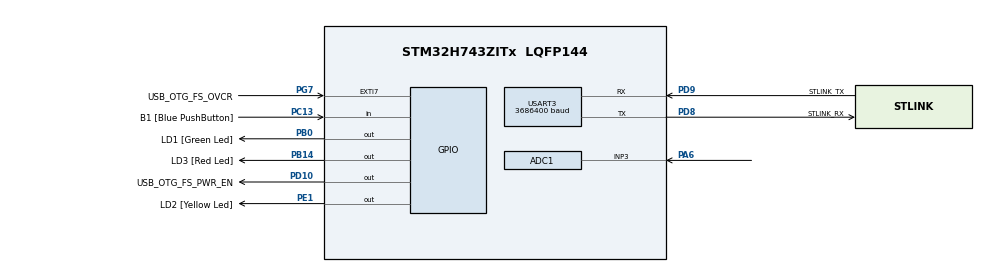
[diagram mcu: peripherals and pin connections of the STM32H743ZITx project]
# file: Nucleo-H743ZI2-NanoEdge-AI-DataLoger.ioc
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ADC1.Channel-0\#ChannelRegularConversion=ADC_CHANNEL_3
ADC1.ExternalTrigConv=ADC_EXTERNALTRIG_T6_TRGO
ADC1.NbrOfConversionFlag=1
ADC1.OffsetNumber-0\#ChannelRegularConversion=ADC_OFFSET_NONE
ADC1.OffsetSignedSaturation-0\#ChannelRegularConversion=DISABLE
ADC1.Rank-0\#ChannelRegularConversion=1
ADC1.Resolution=ADC_RESOLUTION_16B
ADC1.SamplingTime-0\#ChannelRegularConversion=ADC_SAMPLETIME_1CYCLE_5
ADC1.master=1
Mcu.Family=STM32H7
Mcu.Name=STM32H743ZITx
Mcu.Package=LQFP144
NVIC.ADC_IRQn=true\:0\:0\:false\:false\:true\:true\:true\:true
NVIC.PriorityGroup=NVIC_PRIORITYGROUP_4
NVIC.TIM6_DAC_IRQn=true\:0\:0\:false\:false\:true\:true\:true\:true
PA1.Signal=ETH_REF_CLK
PA11.Signal=USB_OTG_FS_DM
PA12.Signal=USB_OTG_FS_DP
PA13\ (JTMS/SWDIO).Mode=Serial_Wire
PA13\ (JTMS/SWDIO).Signal=DEBUG_JTMS-SWDIO
PA14\ (JTCK/SWCLK).Mode=Serial_Wire
PA14\ (JTCK/SWCLK).Signal=DEBUG_JTCK-SWCLK
PA2.Signal=ETH_MDIO
PA6.Signal=ADCx_INP3
PA7.Signal=ETH_CRS_DV
PA8.Signal=USB_OTG_FS_SOF
PA9.Signal=USB_OTG_FS_VBUS
PB0.GPIO_Label=LD1 [Green Led]
PB0.GPIO_Speed=GPIO_SPEED_FREQ_VERY_HIGH
PB0.Signal=GPIO_Output
PB13.Signal=ETH_TXD1
PB14.GPIO_Label=LD3 [Red Led]
PB14.GPIO_Speed=GPIO_SPEED_FREQ_VERY_HIGH
PB14.Signal=GPIO_Output
PC1.Signal=ETH_MDC
PC13.GPIO_Label=B1 [Blue PushButton]
PC13.Signal=GPIO_Input
PC14-OSC32_IN\ (OSC32_IN).Signal=RCC_OSC32_IN
PC15-OSC32_OUT\ (OSC32_OUT).Signal=RCC_OSC32_OUT
PC4.Signal=ETH_RXD0
PC5.Signal=ETH_RXD1
PD10.GPIO_Label=USB_OTG_FS_PWR_EN
PD10.Signal=GPIO_Output
PD8.GPIO_Label=STLINK_RX
PD8.Mode=Asynchronous
PD8.Signal=USART3_TX
PD9.GPIO_Label=STLINK_TX
PD9.Mode=Asynchronous
PD9.Signal=USART3_RX
PE1.GPIO_Label=LD2 [Yellow Led]
PE1.GPIO_Speed=GPIO_SPEED_FREQ_VERY_HIGH
PE1.Signal=GPIO_Output
PG11.Signal=ETH_TX_EN
PG13.Signal=ETH_TXD0
PG7.GPIO_Label=USB_OTG_FS_OVCR
PG7.Signal=GPXTI7
PH0-OSC_IN\ (PH0).Signal=RCC_OSC_IN
PH1-OSC_OUT\ (PH1).Signal=RCC_OSC_OUT
ProjectManager.HeapSize=0x800
ProjectManager.StackSize=0x800
ProjectManager.TargetToolchain=EWARM V8.50
RCC.ADCFreq_Value=100000000
RCC.APB1Freq_Value=120000000
RCC.APB2Freq_Value=120000000
RCC.APB3Freq_Value=120000000
RCC.APB4Freq_Value=120000000
RCC.CortexFreq_Value=480000000
RCC.D1PPRE=RCC_APB3_DIV2
RCC.D2PPRE1=RCC_APB1_DIV2
RCC.D2PPRE2=RCC_APB2_DIV2
RCC.D3PPRE=RCC_APB4_DIV2
RCC.DIVM1=4
RCC.DIVM2=8
RCC.DIVM3=8
RCC.DIVN1=480
RCC.DIVN2=200
RCC.DIVN3=150
RCC.DIVQ1=4
RCC.HCLKFreq_Value=240000000
RCC.HPRE=RCC_HCLK_DIV2
RCC.HSE_VALUE=8000000
RCC.HSIDiv=RCC_PLLSAIDIVR_8
RCC.PLLFRACN=0
RCC.PWR_Regulator_Voltage_Scale=PWR_REGULATOR_VOLTAGE_SCALE0
RCC.SYSCLKFreq_VALUE=480000000
RCC.SYSCLKSource=RCC_SYSCLKSOURCE_PLLCLK
RCC.USBCLockSelection=RCC_USBCLKSOURCE_HSI48
RCC.USBFreq_Value=48000000
SH.ADCx_INP3.0=ADC1_INP3,IN3-Single-Ended
TIM6.Period=39
TIM6.Prescaler=239
TIM6.TIM_MasterOutputTrigger=TIM_TRGO_UPDATE
USART3.BaudRate=3686400
USART3.VirtualMode-Asynchronous=VM_ASYNC
VP_MEMORYMAP_VS_MEMORYMAP.Mode=CurAppReg
VP_TIM6_VS_ClockSourceINT.Mode=Enable_Timer
board=NUCLEO-H743ZI2

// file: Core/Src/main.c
/* USER CODE BEGIN Header */
/**
  ******************************************************************************
  * @file           : main.c
  * @brief          : Main program body
  ******************************************************************************
  * @attention
  *
  * Copyright (c) 2025 STMicroelectronics.
  * All rights reserved.
  *
  * This software is licensed under terms that can be found in the LICENSE file
  * in the root directory of this software component.
  * If no LICENSE file comes with this software, it is provided AS-IS.
  *
  ******************************************************************************
  */
/* USER CODE END Header */
#include "main.h"

/* USER CODE BEGIN Includes */

#include <string.h>
#include <stdio.h>

/* USER CODE END Includes */

ADC_HandleTypeDef hadc1;

TIM_HandleTypeDef htim6;

UART_HandleTypeDef huart3;

void SystemClock_Config(void);
static void MX_GPIO_Init(void);
static void MX_ADC1_Init(void);
static void MX_USART3_UART_Init(void);
static void MX_TIM6_Init(void);

/* USER CODE BEGIN 0 */

//#define TX_BUFFER_SIZE  512U
#define TX_BUFFER_SIZE  1024U
//#define TX_BUFFER_SIZE  4096U

#define ADC_BUF1_SELECT (0)
#define ADC_BUF2_SELECT (1)

uint32_t adc_buf_selector = ADC_BUF1_SELECT;

uint32_t adc_buf_index = 0;

uint32_t adc_buf1[TX_BUFFER_SIZE];
uint32_t adc_buf2[TX_BUFFER_SIZE];

uint32_t adc_buf1_loaded = 0;
uint32_t adc_buf2_loaded = 0;

uint8_t uart_tx_buf[128];

void overload_error(void)
{
    while(1)
    {
        __NOP();
        __NOP();
        __NOP();
        __NOP();
        __NOP();
    }
}

void HAL_TIM_PeriodElapsedCallback(TIM_HandleTypeDef *htim)
{
    if (htim == &htim6)
    {

        // HAL_GPIO_WritePin( LD1_GPIO_Port, LD1_Pin, GPIO_PIN_SET );
        HAL_GPIO_TogglePin( LD1_GPIO_Port, LD1_Pin);

        if ( adc_buf_selector == ADC_BUF1_SELECT )
        {
            adc_buf1[adc_buf_index] = HAL_ADC_GetValue(&hadc1);

            adc_buf_index ++;

            if ( adc_buf_index >= TX_BUFFER_SIZE )
            {
                adc_buf_index = 0;

                if ( adc_buf2_loaded )
                {
                    // ERROR
                    overload_error();
                }

                adc_buf1_loaded = 1;

                adc_buf_selector = ADC_BUF2_SELECT;
            }
        }
        else
        {
            adc_buf2[adc_buf_index] = HAL_ADC_GetValue(&hadc1);

            adc_buf_index ++;

            if ( adc_buf_index >= TX_BUFFER_SIZE )
            {
                adc_buf_index = 0;

                if ( adc_buf1_loaded )
                {
                    // ERROR
                    overload_error();
                }

                adc_buf2_loaded = 1;

                adc_buf_selector = ADC_BUF1_SELECT;
            }
        }

        __NOP();
        __NOP();
        __NOP();
        __NOP();
    }
}

void HAL_ADC_ConvCpltCallback(ADC_HandleTypeDef *hadc)
{
    if (hadc == &hadc1)
    {
        __NOP();
        __NOP();
        __NOP();
        __NOP();
    }
}

uint32_t i = 0;
int msg_len = 0;
GPIO_PinState MyButton;
float Valuefl = 0;

/* USER CODE END 0 */

int main(void)
{

  /* MCU Configuration--------------------------------------------------------*/

  /* Reset of all peripherals, Initializes the Flash interface and the Systick. */
  HAL_Init();

  /* Configure the system clock */
  SystemClock_Config();

  /* Initialize all configured peripherals */
  MX_GPIO_Init();
  MX_ADC1_Init();
  MX_USART3_UART_Init();
  MX_TIM6_Init();

  /* Infinite loop */
  /* USER CODE BEGIN WHILE */

  HAL_ADCEx_Calibration_Start( &hadc1, ADC_CALIB_OFFSET, ADC_SINGLE_ENDED);

  HAL_ADCEx_Calibration_Start( &hadc1, ADC_CALIB_OFFSET_LINEARITY, ADC_SINGLE_ENDED);

  HAL_TIM_Base_Start_IT(&htim6);

  if(HAL_ADC_Start_IT(&hadc1) != HAL_OK)
  {
      Error_Handler();
  }

  while (1)
  {

      MyButton = HAL_GPIO_ReadPin( B1_GPIO_Port, B1_Pin );

      if ( MyButton == GPIO_PIN_RESET )
      {
          HAL_GPIO_WritePin( LD3_GPIO_Port, LD3_Pin, GPIO_PIN_SET );
      }
      else
      {
          HAL_GPIO_WritePin( LD3_GPIO_Port, LD3_Pin, GPIO_PIN_RESET );
      }

      // send ADC data to USART

      // Send buffer 1

      if ( adc_buf1_loaded )
      {
          HAL_GPIO_WritePin(LD2_GPIO_Port, LD2_Pin, GPIO_PIN_RESET);

          for ( i = 0; i < TX_BUFFER_SIZE; i++)
          {
              Valuefl = adc_buf1[i] * (3.3f/65536.0f);

              if ( i < (TX_BUFFER_SIZE-1) )
              {
                  msg_len = sprintf( (char*)uart_tx_buf, "%.4f ", Valuefl) ;

                  HAL_UART_Transmit( &huart3, uart_tx_buf, msg_len, 1 );
              }
              else
              {
                  msg_len = sprintf( (char*)uart_tx_buf, "%.4f\n", Valuefl) ;

                  HAL_UART_Transmit( &huart3, uart_tx_buf, msg_len, 1 );
              }
          }

          adc_buf1_loaded = 0;

          HAL_GPIO_WritePin(LD2_GPIO_Port, LD2_Pin, GPIO_PIN_SET);
      }

       // Send buffer 2

      if ( adc_buf2_loaded )
      {
         HAL_GPIO_WritePin(LD2_GPIO_Port, LD2_Pin, GPIO_PIN_RESET);

          for ( i = 0; i < TX_BUFFER_SIZE; i++)
          {
              Valuefl = adc_buf2[i] * (3.3f/65536.0f);

              if ( i < (TX_BUFFER_SIZE-1) )
              {
                  msg_len = sprintf( (char*)uart_tx_buf, "%.4f ", Valuefl) ;

                  HAL_UART_Transmit( &huart3, uart_tx_buf, msg_len, 1 );
              }
              else
              {
                  msg_len = sprintf( (char*)uart_tx_buf, "%.4f\n", Valuefl) ;

                  HAL_UART_Transmit( &huart3, uart_tx_buf, msg_len, 1 );
              }
          }

          adc_buf2_loaded = 0;

          HAL_GPIO_WritePin(LD2_GPIO_Port, LD2_Pin, GPIO_PIN_SET);
      }

    /* USER CODE END WHILE */

  }
}

void SystemClock_Config(void)
{
  RCC_OscInitTypeDef RCC_OscInitStruct = {0};
  RCC_ClkInitTypeDef RCC_ClkInitStruct = {0};

  /** Supply configuration update enable
  */
  HAL_PWREx_ConfigSupply(PWR_LDO_SUPPLY);

  /** Configure the main internal regulator output voltage
  */
  __HAL_PWR_VOLTAGESCALING_CONFIG(PWR_REGULATOR_VOLTAGE_SCALE1);

  while(!__HAL_PWR_GET_FLAG(PWR_FLAG_VOSRDY)) {}

  __HAL_RCC_SYSCFG_CLK_ENABLE();
  __HAL_PWR_VOLTAGESCALING_CONFIG(PWR_REGULATOR_VOLTAGE_SCALE0);

  while(!__HAL_PWR_GET_FLAG(PWR_FLAG_VOSRDY)) {}

  /** Initializes the RCC Oscillators according to the specified parameters
  * in the RCC_OscInitTypeDef structure.
  */
  RCC_OscInitStruct.OscillatorType = RCC_OSCILLATORTYPE_HSI;
  RCC_OscInitStruct.HSIState = RCC_HSI_DIV8;
  RCC_OscInitStruct.HSICalibrationValue = RCC_HSICALIBRATION_DEFAULT;
  RCC_OscInitStruct.PLL.PLLState = RCC_PLL_ON;
  RCC_OscInitStruct.PLL.PLLSource = RCC_PLLSOURCE_HSI;
  RCC_OscInitStruct.PLL.PLLM = 4;
  RCC_OscInitStruct.PLL.PLLN = 480;
  RCC_OscInitStruct.PLL.PLLP = 2;
  RCC_OscInitStruct.PLL.PLLQ = 4;
  RCC_OscInitStruct.PLL.PLLR = 2;
  RCC_OscInitStruct.PLL.PLLRGE = RCC_PLL1VCIRANGE_1;
  RCC_OscInitStruct.PLL.PLLVCOSEL = RCC_PLL1VCOWIDE;
  RCC_OscInitStruct.PLL.PLLFRACN = 0;
  if (HAL_RCC_OscConfig(&RCC_OscInitStruct) != HAL_OK)
  {
    Error_Handler();
  }

  /** Initializes the CPU, AHB and APB buses clocks
  */
  RCC_ClkInitStruct.ClockType = RCC_CLOCKTYPE_HCLK|RCC_CLOCKTYPE_SYSCLK
                              |RCC_CLOCKTYPE_PCLK1|RCC_CLOCKTYPE_PCLK2
                              |RCC_CLOCKTYPE_D3PCLK1|RCC_CLOCKTYPE_D1PCLK1;
  RCC_ClkInitStruct.SYSCLKSource = RCC_SYSCLKSOURCE_PLLCLK;
  RCC_ClkInitStruct.SYSCLKDivider = RCC_SYSCLK_DIV1;
  RCC_ClkInitStruct.AHBCLKDivider = RCC_HCLK_DIV2;
  RCC_ClkInitStruct.APB3CLKDivider = RCC_APB3_DIV2;
  RCC_ClkInitStruct.APB1CLKDivider = RCC_APB1_DIV2;
  RCC_ClkInitStruct.APB2CLKDivider = RCC_APB2_DIV2;
  RCC_ClkInitStruct.APB4CLKDivider = RCC_APB4_DIV2;

  if (HAL_RCC_ClockConfig(&RCC_ClkInitStruct, FLASH_LATENCY_4) != HAL_OK)
  {
    Error_Handler();
  }
}

static void MX_ADC1_Init(void)
{

  ADC_MultiModeTypeDef multimode = {0};
  ADC_ChannelConfTypeDef sConfig = {0};

  /** Common config
  */
  hadc1.Instance = ADC1;
  hadc1.Init.ScanConvMode = ADC_SCAN_DISABLE;
  hadc1.Init.EOCSelection = ADC_EOC_SINGLE_CONV;
  hadc1.Init.LowPowerAutoWait = DISABLE;
  hadc1.Init.ContinuousConvMode = DISABLE;
  hadc1.Init.NbrOfConversion = 1;
  hadc1.Init.DiscontinuousConvMode = DISABLE;
  hadc1.Init.ExternalTrigConv = ADC_EXTERNALTRIG_T6_TRGO;
  hadc1.Init.ExternalTrigConvEdge = ADC_EXTERNALTRIGCONVEDGE_RISING;
  hadc1.Init.ConversionDataManagement = ADC_CONVERSIONDATA_DR;
  hadc1.Init.Overrun = ADC_OVR_DATA_PRESERVED;
  hadc1.Init.LeftBitShift = ADC_LEFTBITSHIFT_NONE;
  hadc1.Init.OversamplingMode = DISABLE;
  hadc1.Init.Oversampling.Ratio = 1;
  if (HAL_ADC_Init(&hadc1) != HAL_OK)
  {
    Error_Handler();
  }
  hadc1.Init.ClockPrescaler = ADC_CLOCK_ASYNC_DIV1;
  hadc1.Init.Resolution = ADC_RESOLUTION_16B;
  if (HAL_ADC_Init(&hadc1) != HAL_OK)
  {
    Error_Handler();
  }

  /** Configure the ADC multi-mode
  */
  multimode.Mode = ADC_MODE_INDEPENDENT;
  if (HAL_ADCEx_MultiModeConfigChannel(&hadc1, &multimode) != HAL_OK)
  {
    Error_Handler();
  }

  /** Configure Regular Channel
  */
  sConfig.Channel = ADC_CHANNEL_3;
  sConfig.Rank = ADC_REGULAR_RANK_1;
  sConfig.SamplingTime = ADC_SAMPLETIME_1CYCLE_5;
  sConfig.SingleDiff = ADC_SINGLE_ENDED;
  sConfig.OffsetNumber = ADC_OFFSET_NONE;
  sConfig.Offset = 0;
  sConfig.OffsetSignedSaturation = DISABLE;
  if (HAL_ADC_ConfigChannel(&hadc1, &sConfig) != HAL_OK)
  {
    Error_Handler();
  }

}

static void MX_TIM6_Init(void)
{

  TIM_MasterConfigTypeDef sMasterConfig = {0};

  htim6.Instance = TIM6;
  htim6.Init.Prescaler = 239;
  htim6.Init.CounterMode = TIM_COUNTERMODE_UP;
  htim6.Init.Period = 39;
  htim6.Init.AutoReloadPreload = TIM_AUTORELOAD_PRELOAD_DISABLE;
  if (HAL_TIM_Base_Init(&htim6) != HAL_OK)
  {
    Error_Handler();
  }
  sMasterConfig.MasterOutputTrigger = TIM_TRGO_UPDATE;
  sMasterConfig.MasterSlaveMode = TIM_MASTERSLAVEMODE_DISABLE;
  if (HAL_TIMEx_MasterConfigSynchronization(&htim6, &sMasterConfig) != HAL_OK)
  {
    Error_Handler();
  }

}

static void MX_USART3_UART_Init(void)
{

  huart3.Instance = USART3;
  huart3.Init.BaudRate = 3686400;
  huart3.Init.WordLength = UART_WORDLENGTH_8B;
  huart3.Init.StopBits = UART_STOPBITS_1;
  huart3.Init.Parity = UART_PARITY_NONE;
  huart3.Init.Mode = UART_MODE_TX_RX;
  huart3.Init.HwFlowCtl = UART_HWCONTROL_NONE;
  huart3.Init.OverSampling = UART_OVERSAMPLING_16;
  huart3.Init.OneBitSampling = UART_ONE_BIT_SAMPLE_DISABLE;
  huart3.Init.ClockPrescaler = UART_PRESCALER_DIV1;
  huart3.AdvancedInit.AdvFeatureInit = UART_ADVFEATURE_NO_INIT;
  if (HAL_UART_Init(&huart3) != HAL_OK)
  {
    Error_Handler();
  }
  if (HAL_UARTEx_SetTxFifoThreshold(&huart3, UART_TXFIFO_THRESHOLD_1_8) != HAL_OK)
  {
    Error_Handler();
  }
  if (HAL_UARTEx_SetRxFifoThreshold(&huart3, UART_RXFIFO_THRESHOLD_1_8) != HAL_OK)
  {
    Error_Handler();
  }
  if (HAL_UARTEx_DisableFifoMode(&huart3) != HAL_OK)
  {
    Error_Handler();
  }

}

static void MX_GPIO_Init(void)
{
  GPIO_InitTypeDef GPIO_InitStruct = {0};

  /* GPIO Ports Clock Enable */
  __HAL_RCC_GPIOC_CLK_ENABLE();
  __HAL_RCC_GPIOH_CLK_ENABLE();
  __HAL_RCC_GPIOA_CLK_ENABLE();
  __HAL_RCC_GPIOB_CLK_ENABLE();
  __HAL_RCC_GPIOD_CLK_ENABLE();
  __HAL_RCC_GPIOG_CLK_ENABLE();
  __HAL_RCC_GPIOE_CLK_ENABLE();

  /*Configure GPIO pin Output Level */
  HAL_GPIO_WritePin(GPIOB, LD1_Pin|LD3_Pin, GPIO_PIN_RESET);

  /*Configure GPIO pin Output Level */
  HAL_GPIO_WritePin(USB_OTG_FS_PWR_EN_GPIO_Port, USB_OTG_FS_PWR_EN_Pin, GPIO_PIN_RESET);

  /*Configure GPIO pin Output Level */
  HAL_GPIO_WritePin(LD2_GPIO_Port, LD2_Pin, GPIO_PIN_RESET);

  /*Configure GPIO pin : B1_Pin */
  GPIO_InitStruct.Pin = B1_Pin;
  GPIO_InitStruct.Mode = GPIO_MODE_INPUT;
  GPIO_InitStruct.Pull = GPIO_NOPULL;
  HAL_GPIO_Init(B1_GPIO_Port, &GPIO_InitStruct);

  /*Configure GPIO pins : PC1 PC4 PC5 */
  GPIO_InitStruct.Pin = GPIO_PIN_1|GPIO_PIN_4|GPIO_PIN_5;
  GPIO_InitStruct.Mode = GPIO_MODE_AF_PP;
  GPIO_InitStruct.Pull = GPIO_NOPULL;
  GPIO_InitStruct.Speed = GPIO_SPEED_FREQ_LOW;
  GPIO_InitStruct.Alternate = GPIO_AF11_ETH;
  HAL_GPIO_Init(GPIOC, &GPIO_InitStruct);

  /*Configure GPIO pins : PA1 PA2 PA7 */
  GPIO_InitStruct.Pin = GPIO_PIN_1|GPIO_PIN_2|GPIO_PIN_7;
  GPIO_InitStruct.Mode = GPIO_MODE_AF_PP;
  GPIO_InitStruct.Pull = GPIO_NOPULL;
  GPIO_InitStruct.Speed = GPIO_SPEED_FREQ_LOW;
  GPIO_InitStruct.Alternate = GPIO_AF11_ETH;
  HAL_GPIO_Init(GPIOA, &GPIO_InitStruct);

  /*Configure GPIO pins : LD1_Pin LD3_Pin */
  GPIO_InitStruct.Pin = LD1_Pin|LD3_Pin;
  GPIO_InitStruct.Mode = GPIO_MODE_OUTPUT_PP;
  GPIO_InitStruct.Pull = GPIO_NOPULL;
  GPIO_InitStruct.Speed = GPIO_SPEED_FREQ_VERY_HIGH;
  HAL_GPIO_Init(GPIOB, &GPIO_InitStruct);

  /*Configure GPIO pin : PB13 */
  GPIO_InitStruct.Pin = GPIO_PIN_13;
  GPIO_InitStruct.Mode = GPIO_MODE_AF_PP;
  GPIO_InitStruct.Pull = GPIO_NOPULL;
  GPIO_InitStruct.Speed = GPIO_SPEED_FREQ_LOW;
  GPIO_InitStruct.Alternate = GPIO_AF11_ETH;
  HAL_GPIO_Init(GPIOB, &GPIO_InitStruct);

  /*Configure GPIO pin : USB_OTG_FS_PWR_EN_Pin */
  GPIO_InitStruct.Pin = USB_OTG_FS_PWR_EN_Pin;
  GPIO_InitStruct.Mode = GPIO_MODE_OUTPUT_PP;
  GPIO_InitStruct.Pull = GPIO_NOPULL;
  GPIO_InitStruct.Speed = GPIO_SPEED_FREQ_LOW;
  HAL_GPIO_Init(USB_OTG_FS_PWR_EN_GPIO_Port, &GPIO_InitStruct);

  /*Configure GPIO pin : USB_OTG_FS_OVCR_Pin */
  GPIO_InitStruct.Pin = USB_OTG_FS_OVCR_Pin;
  GPIO_InitStruct.Mode = GPIO_MODE_IT_RISING;
  GPIO_InitStruct.Pull = GPIO_NOPULL;
  HAL_GPIO_Init(USB_OTG_FS_OVCR_GPIO_Port, &GPIO_InitStruct);

  /*Configure GPIO pins : PA8 PA11 PA12 */
  GPIO_InitStruct.Pin = GPIO_PIN_8|GPIO_PIN_11|GPIO_PIN_12;
  GPIO_InitStruct.Mode = GPIO_MODE_AF_PP;
  GPIO_InitStruct.Pull = GPIO_NOPULL;
  GPIO_InitStruct.Speed = GPIO_SPEED_FREQ_LOW;
  GPIO_InitStruct.Alternate = GPIO_AF10_OTG1_FS;
  HAL_GPIO_Init(GPIOA, &GPIO_InitStruct);

  /*Configure GPIO pins : PG11 PG13 */
  GPIO_InitStruct.Pin = GPIO_PIN_11|GPIO_PIN_13;
  GPIO_InitStruct.Mode = GPIO_MODE_AF_PP;
  GPIO_InitStruct.Pull = GPIO_NOPULL;
  GPIO_InitStruct.Speed = GPIO_SPEED_FREQ_LOW;
  GPIO_InitStruct.Alternate = GPIO_AF11_ETH;
  HAL_GPIO_Init(GPIOG, &GPIO_InitStruct);

  /*Configure GPIO pin : LD2_Pin */
  GPIO_InitStruct.Pin = LD2_Pin;
  GPIO_InitStruct.Mode = GPIO_MODE_OUTPUT_PP;
  GPIO_InitStruct.Pull = GPIO_NOPULL;
  GPIO_InitStruct.Speed = GPIO_SPEED_FREQ_VERY_HIGH;
  HAL_GPIO_Init(LD2_GPIO_Port, &GPIO_InitStruct);

}

void Error_Handler(void)
{
  __disable_irq();
  while (1)
  {
  }
}
